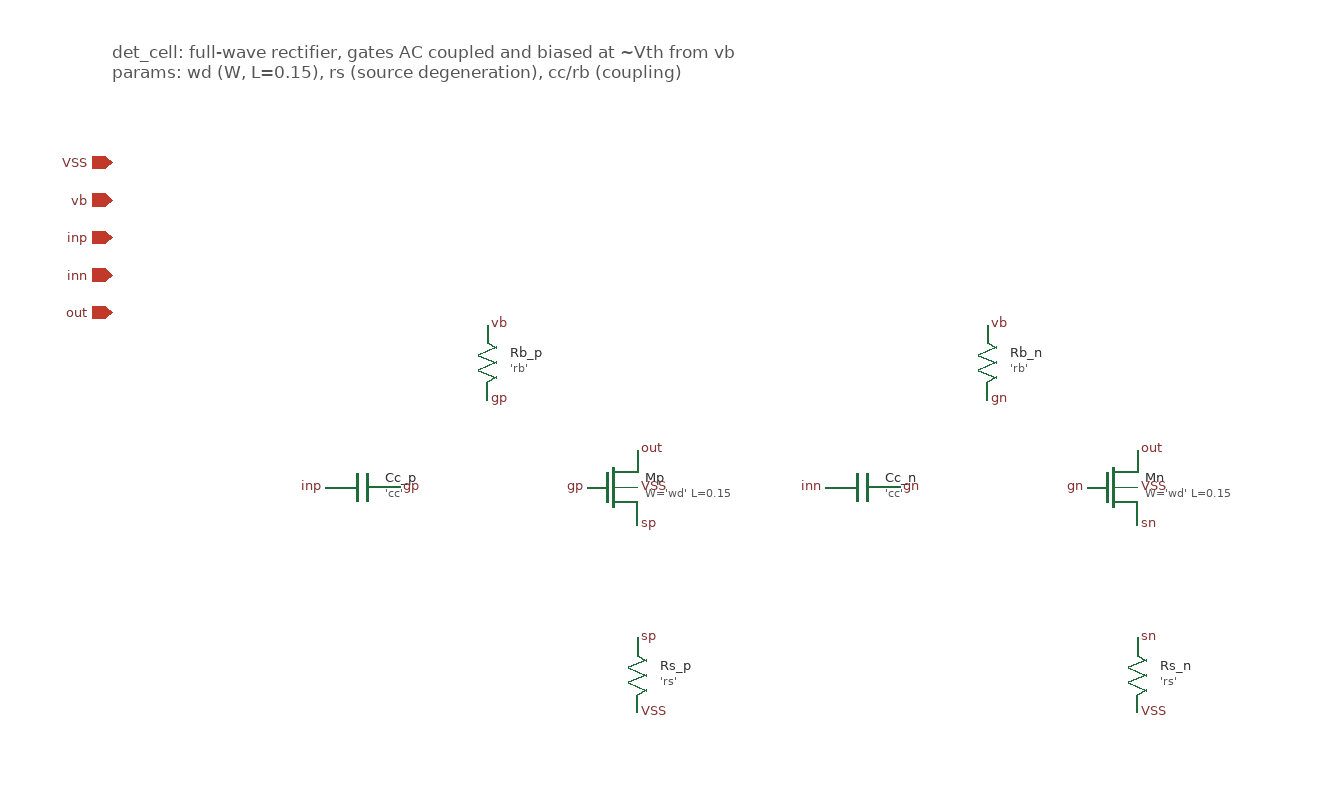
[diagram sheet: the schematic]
v {xschem version=3.4.5 file_version=1.2
}
G {}
K {}
V {}
S {}
E {}
T {det_cell: full-wave rectifier, gates AC coupled and biased at ~Vth from vb
params: wd (W, L=0.15), rs (source degeneration), cc/rb (coupling)} -400 -560 0 0 0.4 0.4 {}
C {devices/iopin.sym} -400 -460 0 0 {name=p1
lab=VSS}
C {devices/iopin.sym} -400 -430 0 0 {name=p2
lab=vb}
C {devices/iopin.sym} -400 -400 0 0 {name=p3
lab=inp}
C {devices/iopin.sym} -400 -370 0 0 {name=p4
lab=inn}
C {devices/iopin.sym} -400 -340 0 0 {name=p5
lab=out}
C {devices/capa.sym} -200 -200 1 0 {name=Cc_p
value='cc'
m=1}
C {devices/lab_pin.sym} -170 -200 0 1 {name=p6
sig_type=std_logic
lab=gp}
C {devices/lab_pin.sym} -230 -200 0 0 {name=p7
sig_type=std_logic
lab=inp}
C {devices/res.sym} -100 -300 0 0 {name=Rb_p
value='rb'
m=1}
C {devices/lab_pin.sym} -100 -330 0 1 {name=p8
sig_type=std_logic
lab=vb}
C {devices/lab_pin.sym} -100 -270 0 1 {name=p9
sig_type=std_logic
lab=gp}
C {sky130_fd_pr/nfet_01v8.sym} 0 -200 0 0 {name=Mp
nf=1
mult=1
ad="'int((nf+1)/2) * W/nf * 0.29'"
pd="'2*int((nf+1)/2) * (W/nf + 0.29)'"
as="'int((nf+2)/2) * W/nf * 0.29'"
ps="'2*int((nf+2)/2) * (W/nf + 0.29)'"
nrd="'0.29 / W'"
nrs="'0.29 / W'"
sa=0
sb=0
sd=0
L=0.15
W='wd'
model=nfet_01v8
spiceprefix=X}
C {devices/lab_pin.sym} 20 -230 0 1 {name=p10
sig_type=std_logic
lab=out}
C {devices/lab_pin.sym} -20 -200 0 0 {name=p11
sig_type=std_logic
lab=gp}
C {devices/lab_pin.sym} 20 -170 0 1 {name=p12
sig_type=std_logic
lab=sp}
C {devices/lab_pin.sym} 20 -200 0 1 {name=p13
sig_type=std_logic
lab=VSS}
C {devices/res.sym} 20 -50 0 0 {name=Rs_p
value='rs'
m=1}
C {devices/lab_pin.sym} 20 -80 0 1 {name=p14
sig_type=std_logic
lab=sp}
C {devices/lab_pin.sym} 20 -20 0 1 {name=p15
sig_type=std_logic
lab=VSS}
C {devices/capa.sym} 200 -200 1 0 {name=Cc_n
value='cc'
m=1}
C {devices/lab_pin.sym} 230 -200 0 1 {name=p16
sig_type=std_logic
lab=gn}
C {devices/lab_pin.sym} 170 -200 0 0 {name=p17
sig_type=std_logic
lab=inn}
C {devices/res.sym} 300 -300 0 0 {name=Rb_n
value='rb'
m=1}
C {devices/lab_pin.sym} 300 -330 0 1 {name=p18
sig_type=std_logic
lab=vb}
C {devices/lab_pin.sym} 300 -270 0 1 {name=p19
sig_type=std_logic
lab=gn}
C {sky130_fd_pr/nfet_01v8.sym} 400 -200 0 0 {name=Mn
nf=1
mult=1
ad="'int((nf+1)/2) * W/nf * 0.29'"
pd="'2*int((nf+1)/2) * (W/nf + 0.29)'"
as="'int((nf+2)/2) * W/nf * 0.29'"
ps="'2*int((nf+2)/2) * (W/nf + 0.29)'"
nrd="'0.29 / W'"
nrs="'0.29 / W'"
sa=0
sb=0
sd=0
L=0.15
W='wd'
model=nfet_01v8
spiceprefix=X}
C {devices/lab_pin.sym} 420 -230 0 1 {name=p20
sig_type=std_logic
lab=out}
C {devices/lab_pin.sym} 380 -200 0 0 {name=p21
sig_type=std_logic
lab=gn}
C {devices/lab_pin.sym} 420 -170 0 1 {name=p22
sig_type=std_logic
lab=sn}
C {devices/lab_pin.sym} 420 -200 0 1 {name=p23
sig_type=std_logic
lab=VSS}
C {devices/res.sym} 420 -50 0 0 {name=Rs_n
value='rs'
m=1}
C {devices/lab_pin.sym} 420 -80 0 1 {name=p24
sig_type=std_logic
lab=sn}
C {devices/lab_pin.sym} 420 -20 0 1 {name=p25
sig_type=std_logic
lab=VSS}
